One B-rep face of a CAD part: STEP entity #1141.
In plain terms, the cylindrical face has radius 42.5 mm (diameter 85 mm), a partial arc.
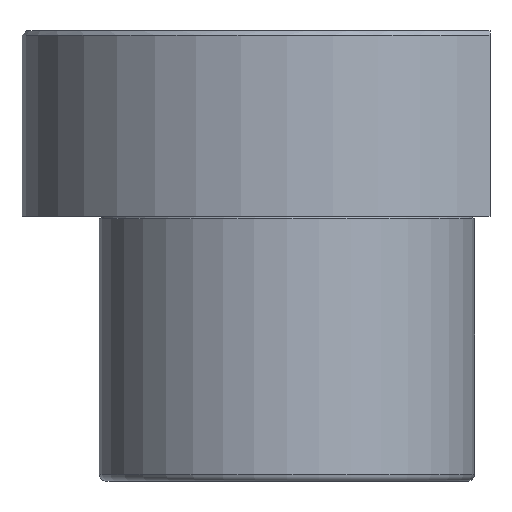
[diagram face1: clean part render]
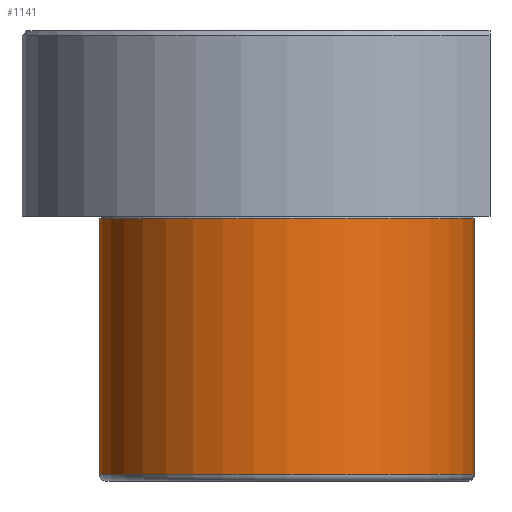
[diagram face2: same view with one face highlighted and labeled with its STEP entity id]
Its self-contained STEP definition (entity closure, numbers rounded to 3 decimals):
#953=CARTESIAN_POINT('Vertex',(42.5,0.,-0.6)) ;
#955=CARTESIAN_POINT('Vertex',(-42.5,0.,-0.6)) ;
#980=CARTESIAN_POINT('Axis2P3D Location',(0.,0.,-0.6)) ;
#1087=CARTESIAN_POINT('Line Origine',(-42.5,0.,42.)) ;
#1091=CARTESIAN_POINT('Vertex',(-42.5,0.,-58.4)) ;
#1094=CARTESIAN_POINT('Line Origine',(42.5,0.,42.)) ;
#1098=CARTESIAN_POINT('Vertex',(42.5,0.,-58.4)) ;
#1125=CARTESIAN_POINT('Axis2P3D Location',(0.,0.,42.)) ;
#1130=CARTESIAN_POINT('Axis2P3D Location',(0.,0.,-58.4)) ;
#981=DIRECTION('Axis2P3D Direction',(0.,-0.,1.)) ;
#1088=DIRECTION('Vector Direction',(0.,0.,-1.)) ;
#1095=DIRECTION('Vector Direction',(0.,0.,-1.)) ;
#1126=DIRECTION('Axis2P3D Direction',(0.,0.,-1.)) ;
#1127=DIRECTION('Axis2P3D XDirection',(1.,0.,0.)) ;
#1131=DIRECTION('Axis2P3D Direction',(0.,0.,-1.)) ;
#982=AXIS2_PLACEMENT_3D('Circle Axis2P3D',#980,#981,$) ;
#1128=AXIS2_PLACEMENT_3D('Cylinder Axis2P3D',#1125,#1126,#1127) ;
#1132=AXIS2_PLACEMENT_3D('Circle Axis2P3D',#1130,#1131,$) ;
#1136=ORIENTED_EDGE('',*,*,#1100,.T.) ;
#1137=ORIENTED_EDGE('',*,*,#984,.F.) ;
#1138=ORIENTED_EDGE('',*,*,#1093,.T.) ;
#1139=ORIENTED_EDGE('',*,*,#1134,.T.) ;
#1089=VECTOR('Line Direction',#1088,1.) ;
#1096=VECTOR('Line Direction',#1095,1.) ;
#1141=ADVANCED_FACE('737-63',(#1140),#1129,.T.) ;
#983=CIRCLE('generated circle',#982,42.5) ;
#1133=CIRCLE('generated circle',#1132,42.5) ;
#1129=CYLINDRICAL_SURFACE('generated cylinder',#1128,42.5) ;
#984=EDGE_CURVE('',#956,#954,#983,.T.) ;
#1093=EDGE_CURVE('',#956,#1092,#1090,.T.) ;
#1100=EDGE_CURVE('',#1099,#954,#1097,.F.) ;
#1134=EDGE_CURVE('',#1092,#1099,#1133,.F.) ;
#1135=EDGE_LOOP('',(#1136,#1137,#1138,#1139)) ;
#1140=FACE_OUTER_BOUND('',#1135,.T.) ;
#1090=LINE('Line',#1087,#1089) ;
#1097=LINE('Line',#1094,#1096) ;
#954=VERTEX_POINT('',#953) ;
#956=VERTEX_POINT('',#955) ;
#1092=VERTEX_POINT('',#1091) ;
#1099=VERTEX_POINT('',#1098) ;
